VERSION 5.7 ;
  NOWIREEXTENSIONATPIN ON ;
  DIVIDERCHAR "/" ;
  BUSBITCHARS "[]" ;
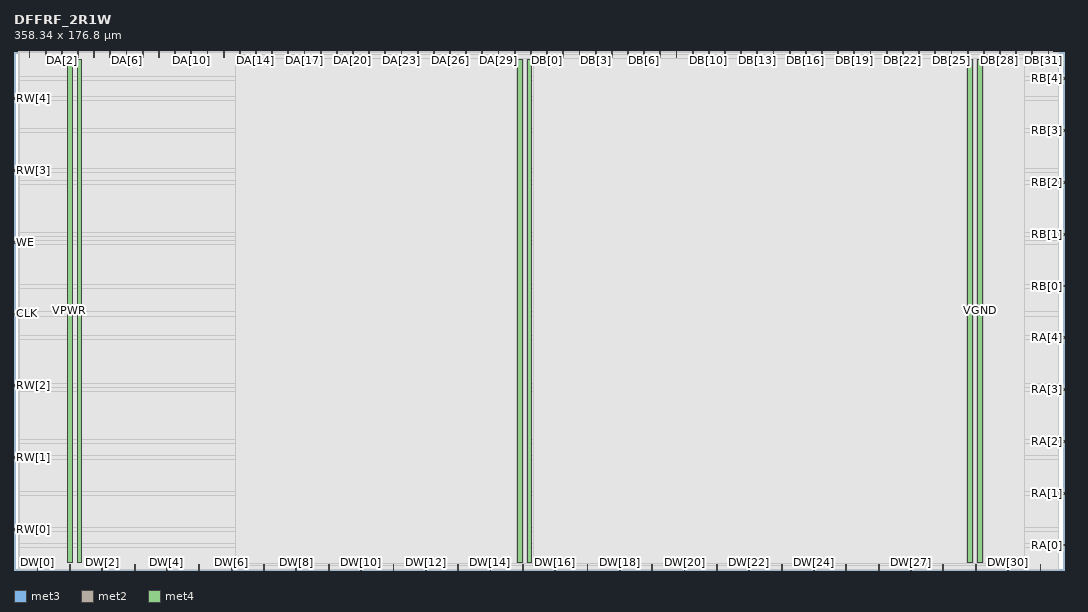
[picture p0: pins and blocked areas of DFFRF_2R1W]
MACRO DFFRF_2R1W
  CLASS BLOCK ;
  FOREIGN DFFRF_2R1W ;
  ORIGIN 0.000 0.000 ;
  SIZE 358.340 BY 176.800 ;
  PIN CLK
    DIRECTION INPUT ;
    USE SIGNAL ;
    ANTENNAGATEAREA 39.431999 ;
    PORT
      LAYER met3 ;
        RECT 0.000 87.080 2.000 87.680 ;
    END
  END CLK
  PIN DA[0]
    DIRECTION OUTPUT ;
    USE SIGNAL ;
    ANTENNADIFFAREA 14.256000 ;
    PORT
      LAYER met2 ;
        RECT 5.150 174.800 5.430 176.800 ;
    END
  END DA[0]
  PIN DA[10]
    DIRECTION OUTPUT ;
    USE SIGNAL ;
    ANTENNADIFFAREA 14.256000 ;
    PORT
      LAYER met2 ;
        RECT 60.350 174.800 60.630 176.800 ;
    END
  END DA[10]
  PIN DA[11]
    DIRECTION OUTPUT ;
    USE SIGNAL ;
    ANTENNADIFFAREA 14.256000 ;
    PORT
      LAYER met2 ;
        RECT 65.870 174.800 66.150 176.800 ;
    END
  END DA[11]
  PIN DA[12]
    DIRECTION OUTPUT ;
    USE SIGNAL ;
    ANTENNADIFFAREA 14.256000 ;
    PORT
      LAYER met2 ;
        RECT 71.390 174.800 71.670 176.800 ;
    END
  END DA[12]
  PIN DA[13]
    DIRECTION OUTPUT ;
    USE SIGNAL ;
    ANTENNADIFFAREA 14.256000 ;
    PORT
      LAYER met2 ;
        RECT 76.910 174.800 77.190 176.800 ;
    END
  END DA[13]
  PIN DA[14]
    DIRECTION OUTPUT ;
    USE SIGNAL ;
    ANTENNADIFFAREA 14.256000 ;
    PORT
      LAYER met2 ;
        RECT 82.430 174.800 82.710 176.800 ;
    END
  END DA[14]
  PIN DA[15]
    DIRECTION OUTPUT ;
    USE SIGNAL ;
    ANTENNADIFFAREA 14.256000 ;
    PORT
      LAYER met2 ;
        RECT 87.950 174.800 88.230 176.800 ;
    END
  END DA[15]
  PIN DA[16]
    DIRECTION OUTPUT ;
    USE SIGNAL ;
    ANTENNADIFFAREA 14.256000 ;
    PORT
      LAYER met2 ;
        RECT 93.470 174.800 93.750 176.800 ;
    END
  END DA[16]
  PIN DA[17]
    DIRECTION OUTPUT ;
    USE SIGNAL ;
    ANTENNADIFFAREA 14.256000 ;
    PORT
      LAYER met2 ;
        RECT 98.990 174.800 99.270 176.800 ;
    END
  END DA[17]
  PIN DA[18]
    DIRECTION OUTPUT ;
    USE SIGNAL ;
    ANTENNADIFFAREA 14.256000 ;
    PORT
      LAYER met2 ;
        RECT 104.510 174.800 104.790 176.800 ;
    END
  END DA[18]
  PIN DA[19]
    DIRECTION OUTPUT ;
    USE SIGNAL ;
    ANTENNADIFFAREA 14.256000 ;
    PORT
      LAYER met2 ;
        RECT 110.030 174.800 110.310 176.800 ;
    END
  END DA[19]
  PIN DA[1]
    DIRECTION OUTPUT ;
    USE SIGNAL ;
    ANTENNADIFFAREA 14.256000 ;
    PORT
      LAYER met2 ;
        RECT 10.670 174.800 10.950 176.800 ;
    END
  END DA[1]
  PIN DA[20]
    DIRECTION OUTPUT ;
    USE SIGNAL ;
    ANTENNADIFFAREA 14.256000 ;
    PORT
      LAYER met2 ;
        RECT 115.550 174.800 115.830 176.800 ;
    END
  END DA[20]
  PIN DA[21]
    DIRECTION OUTPUT ;
    USE SIGNAL ;
    ANTENNADIFFAREA 14.256000 ;
    PORT
      LAYER met2 ;
        RECT 121.070 174.800 121.350 176.800 ;
    END
  END DA[21]
  PIN DA[22]
    DIRECTION OUTPUT ;
    USE SIGNAL ;
    ANTENNADIFFAREA 14.256000 ;
    PORT
      LAYER met2 ;
        RECT 126.590 174.800 126.870 176.800 ;
    END
  END DA[22]
  PIN DA[23]
    DIRECTION OUTPUT ;
    USE SIGNAL ;
    ANTENNADIFFAREA 14.256000 ;
    PORT
      LAYER met2 ;
        RECT 132.110 174.800 132.390 176.800 ;
    END
  END DA[23]
  PIN DA[24]
    DIRECTION OUTPUT ;
    USE SIGNAL ;
    ANTENNADIFFAREA 14.256000 ;
    PORT
      LAYER met2 ;
        RECT 137.630 174.800 137.910 176.800 ;
    END
  END DA[24]
  PIN DA[25]
    DIRECTION OUTPUT ;
    USE SIGNAL ;
    ANTENNADIFFAREA 14.256000 ;
    PORT
      LAYER met2 ;
        RECT 143.150 174.800 143.430 176.800 ;
    END
  END DA[25]
  PIN DA[26]
    DIRECTION OUTPUT ;
    USE SIGNAL ;
    ANTENNADIFFAREA 14.256000 ;
    PORT
      LAYER met2 ;
        RECT 148.670 174.800 148.950 176.800 ;
    END
  END DA[26]
  PIN DA[27]
    DIRECTION OUTPUT ;
    USE SIGNAL ;
    ANTENNADIFFAREA 14.256000 ;
    PORT
      LAYER met2 ;
        RECT 154.190 174.800 154.470 176.800 ;
    END
  END DA[27]
  PIN DA[28]
    DIRECTION OUTPUT ;
    USE SIGNAL ;
    ANTENNADIFFAREA 14.256000 ;
    PORT
      LAYER met2 ;
        RECT 159.710 174.800 159.990 176.800 ;
    END
  END DA[28]
  PIN DA[29]
    DIRECTION OUTPUT ;
    USE SIGNAL ;
    ANTENNADIFFAREA 14.256000 ;
    PORT
      LAYER met2 ;
        RECT 165.230 174.800 165.510 176.800 ;
    END
  END DA[29]
  PIN DA[2]
    DIRECTION OUTPUT ;
    USE SIGNAL ;
    ANTENNADIFFAREA 14.256000 ;
    PORT
      LAYER met2 ;
        RECT 16.190 174.800 16.470 176.800 ;
    END
  END DA[2]
  PIN DA[30]
    DIRECTION OUTPUT ;
    USE SIGNAL ;
    ANTENNADIFFAREA 14.256000 ;
    PORT
      LAYER met2 ;
        RECT 170.750 174.800 171.030 176.800 ;
    END
  END DA[30]
  PIN DA[31]
    DIRECTION OUTPUT ;
    USE SIGNAL ;
    ANTENNADIFFAREA 14.256000 ;
    PORT
      LAYER met2 ;
        RECT 176.270 174.800 176.550 176.800 ;
    END
  END DA[31]
  PIN DA[3]
    DIRECTION OUTPUT ;
    USE SIGNAL ;
    ANTENNADIFFAREA 14.256000 ;
    PORT
      LAYER met2 ;
        RECT 21.710 174.800 21.990 176.800 ;
    END
  END DA[3]
  PIN DA[4]
    DIRECTION OUTPUT ;
    USE SIGNAL ;
    ANTENNADIFFAREA 14.256000 ;
    PORT
      LAYER met2 ;
        RECT 27.230 174.800 27.510 176.800 ;
    END
  END DA[4]
  PIN DA[5]
    DIRECTION OUTPUT ;
    USE SIGNAL ;
    ANTENNADIFFAREA 14.256000 ;
    PORT
      LAYER met2 ;
        RECT 32.750 174.800 33.030 176.800 ;
    END
  END DA[5]
  PIN DA[6]
    DIRECTION OUTPUT ;
    USE SIGNAL ;
    ANTENNADIFFAREA 14.256000 ;
    PORT
      LAYER met2 ;
        RECT 38.270 174.800 38.550 176.800 ;
    END
  END DA[6]
  PIN DA[7]
    DIRECTION OUTPUT ;
    USE SIGNAL ;
    ANTENNADIFFAREA 14.256000 ;
    PORT
      LAYER met2 ;
        RECT 43.790 174.800 44.070 176.800 ;
    END
  END DA[7]
  PIN DA[8]
    DIRECTION OUTPUT ;
    USE SIGNAL ;
    ANTENNADIFFAREA 14.256000 ;
    PORT
      LAYER met2 ;
        RECT 49.310 174.800 49.590 176.800 ;
    END
  END DA[8]
  PIN DA[9]
    DIRECTION OUTPUT ;
    USE SIGNAL ;
    ANTENNADIFFAREA 14.256000 ;
    PORT
      LAYER met2 ;
        RECT 54.830 174.800 55.110 176.800 ;
    END
  END DA[9]
  PIN DB[0]
    DIRECTION OUTPUT ;
    USE SIGNAL ;
    ANTENNADIFFAREA 14.256000 ;
    PORT
      LAYER met2 ;
        RECT 181.790 174.800 182.070 176.800 ;
    END
  END DB[0]
  PIN DB[10]
    DIRECTION OUTPUT ;
    USE SIGNAL ;
    ANTENNADIFFAREA 14.256000 ;
    PORT
      LAYER met2 ;
        RECT 236.990 174.800 237.270 176.800 ;
    END
  END DB[10]
  PIN DB[11]
    DIRECTION OUTPUT ;
    USE SIGNAL ;
    ANTENNADIFFAREA 14.256000 ;
    PORT
      LAYER met2 ;
        RECT 242.510 174.800 242.790 176.800 ;
    END
  END DB[11]
  PIN DB[12]
    DIRECTION OUTPUT ;
    USE SIGNAL ;
    ANTENNADIFFAREA 14.256000 ;
    PORT
      LAYER met2 ;
        RECT 248.030 174.800 248.310 176.800 ;
    END
  END DB[12]
  PIN DB[13]
    DIRECTION OUTPUT ;
    USE SIGNAL ;
    ANTENNADIFFAREA 14.256000 ;
    PORT
      LAYER met2 ;
        RECT 253.550 174.800 253.830 176.800 ;
    END
  END DB[13]
  PIN DB[14]
    DIRECTION OUTPUT ;
    USE SIGNAL ;
    ANTENNADIFFAREA 14.256000 ;
    PORT
      LAYER met2 ;
        RECT 259.070 174.800 259.350 176.800 ;
    END
  END DB[14]
  PIN DB[15]
    DIRECTION OUTPUT ;
    USE SIGNAL ;
    ANTENNADIFFAREA 14.256000 ;
    PORT
      LAYER met2 ;
        RECT 264.590 174.800 264.870 176.800 ;
    END
  END DB[15]
  PIN DB[16]
    DIRECTION OUTPUT ;
    USE SIGNAL ;
    ANTENNADIFFAREA 14.256000 ;
    PORT
      LAYER met2 ;
        RECT 270.110 174.800 270.390 176.800 ;
    END
  END DB[16]
  PIN DB[17]
    DIRECTION OUTPUT ;
    USE SIGNAL ;
    ANTENNADIFFAREA 14.256000 ;
    PORT
      LAYER met2 ;
        RECT 275.630 174.800 275.910 176.800 ;
    END
  END DB[17]
  PIN DB[18]
    DIRECTION OUTPUT ;
    USE SIGNAL ;
    ANTENNADIFFAREA 14.256000 ;
    PORT
      LAYER met2 ;
        RECT 281.150 174.800 281.430 176.800 ;
    END
  END DB[18]
  PIN DB[19]
    DIRECTION OUTPUT ;
    USE SIGNAL ;
    ANTENNADIFFAREA 14.256000 ;
    PORT
      LAYER met2 ;
        RECT 286.670 174.800 286.950 176.800 ;
    END
  END DB[19]
  PIN DB[1]
    DIRECTION OUTPUT ;
    USE SIGNAL ;
    ANTENNADIFFAREA 14.256000 ;
    PORT
      LAYER met2 ;
        RECT 187.310 174.800 187.590 176.800 ;
    END
  END DB[1]
  PIN DB[20]
    DIRECTION OUTPUT ;
    USE SIGNAL ;
    ANTENNADIFFAREA 14.256000 ;
    PORT
      LAYER met2 ;
        RECT 292.190 174.800 292.470 176.800 ;
    END
  END DB[20]
  PIN DB[21]
    DIRECTION OUTPUT ;
    USE SIGNAL ;
    ANTENNADIFFAREA 14.256000 ;
    PORT
      LAYER met2 ;
        RECT 297.710 174.800 297.990 176.800 ;
    END
  END DB[21]
  PIN DB[22]
    DIRECTION OUTPUT ;
    USE SIGNAL ;
    ANTENNADIFFAREA 14.256000 ;
    PORT
      LAYER met2 ;
        RECT 303.230 174.800 303.510 176.800 ;
    END
  END DB[22]
  PIN DB[23]
    DIRECTION OUTPUT ;
    USE SIGNAL ;
    ANTENNADIFFAREA 14.256000 ;
    PORT
      LAYER met2 ;
        RECT 308.750 174.800 309.030 176.800 ;
    END
  END DB[23]
  PIN DB[24]
    DIRECTION OUTPUT ;
    USE SIGNAL ;
    ANTENNADIFFAREA 14.256000 ;
    PORT
      LAYER met2 ;
        RECT 314.270 174.800 314.550 176.800 ;
    END
  END DB[24]
  PIN DB[25]
    DIRECTION OUTPUT ;
    USE SIGNAL ;
    ANTENNADIFFAREA 14.256000 ;
    PORT
      LAYER met2 ;
        RECT 319.790 174.800 320.070 176.800 ;
    END
  END DB[25]
  PIN DB[26]
    DIRECTION OUTPUT ;
    USE SIGNAL ;
    ANTENNADIFFAREA 14.256000 ;
    PORT
      LAYER met2 ;
        RECT 325.310 174.800 325.590 176.800 ;
    END
  END DB[26]
  PIN DB[27]
    DIRECTION OUTPUT ;
    USE SIGNAL ;
    ANTENNADIFFAREA 14.256000 ;
    PORT
      LAYER met2 ;
        RECT 330.830 174.800 331.110 176.800 ;
    END
  END DB[27]
  PIN DB[28]
    DIRECTION OUTPUT ;
    USE SIGNAL ;
    ANTENNADIFFAREA 14.256000 ;
    PORT
      LAYER met2 ;
        RECT 336.350 174.800 336.630 176.800 ;
    END
  END DB[28]
  PIN DB[29]
    DIRECTION OUTPUT ;
    USE SIGNAL ;
    ANTENNADIFFAREA 14.256000 ;
    PORT
      LAYER met2 ;
        RECT 341.870 174.800 342.150 176.800 ;
    END
  END DB[29]
  PIN DB[2]
    DIRECTION OUTPUT ;
    USE SIGNAL ;
    ANTENNADIFFAREA 14.256000 ;
    PORT
      LAYER met2 ;
        RECT 192.830 174.800 193.110 176.800 ;
    END
  END DB[2]
  PIN DB[30]
    DIRECTION OUTPUT ;
    USE SIGNAL ;
    ANTENNADIFFAREA 14.256000 ;
    PORT
      LAYER met2 ;
        RECT 347.390 174.800 347.670 176.800 ;
    END
  END DB[30]
  PIN DB[31]
    DIRECTION OUTPUT ;
    USE SIGNAL ;
    ANTENNADIFFAREA 14.256000 ;
    PORT
      LAYER met2 ;
        RECT 352.910 174.800 353.190 176.800 ;
    END
  END DB[31]
  PIN DB[3]
    DIRECTION OUTPUT ;
    USE SIGNAL ;
    ANTENNADIFFAREA 14.256000 ;
    PORT
      LAYER met2 ;
        RECT 198.350 174.800 198.630 176.800 ;
    END
  END DB[3]
  PIN DB[4]
    DIRECTION OUTPUT ;
    USE SIGNAL ;
    ANTENNADIFFAREA 14.256000 ;
    PORT
      LAYER met2 ;
        RECT 203.870 174.800 204.150 176.800 ;
    END
  END DB[4]
  PIN DB[5]
    DIRECTION OUTPUT ;
    USE SIGNAL ;
    ANTENNADIFFAREA 14.256000 ;
    PORT
      LAYER met2 ;
        RECT 209.390 174.800 209.670 176.800 ;
    END
  END DB[5]
  PIN DB[6]
    DIRECTION OUTPUT ;
    USE SIGNAL ;
    ANTENNADIFFAREA 14.256000 ;
    PORT
      LAYER met2 ;
        RECT 214.910 174.800 215.190 176.800 ;
    END
  END DB[6]
  PIN DB[7]
    DIRECTION OUTPUT ;
    USE SIGNAL ;
    ANTENNADIFFAREA 14.256000 ;
    PORT
      LAYER met2 ;
        RECT 220.430 174.800 220.710 176.800 ;
    END
  END DB[7]
  PIN DB[8]
    DIRECTION OUTPUT ;
    USE SIGNAL ;
    ANTENNADIFFAREA 14.256000 ;
    PORT
      LAYER met2 ;
        RECT 225.950 174.800 226.230 176.800 ;
    END
  END DB[8]
  PIN DB[9]
    DIRECTION OUTPUT ;
    USE SIGNAL ;
    ANTENNADIFFAREA 14.256000 ;
    PORT
      LAYER met2 ;
        RECT 231.470 174.800 231.750 176.800 ;
    END
  END DB[9]
  PIN DW[0]
    DIRECTION INPUT ;
    USE SIGNAL ;
    ANTENNAGATEAREA 3.906000 ;
    PORT
      LAYER met2 ;
        RECT 7.910 0.000 8.190 2.000 ;
    END
  END DW[0]
  PIN DW[10]
    DIRECTION INPUT ;
    USE SIGNAL ;
    ANTENNAGATEAREA 3.906000 ;
    PORT
      LAYER met2 ;
        RECT 118.310 0.000 118.590 2.000 ;
    END
  END DW[10]
  PIN DW[11]
    DIRECTION INPUT ;
    USE SIGNAL ;
    ANTENNAGATEAREA 3.906000 ;
    PORT
      LAYER met2 ;
        RECT 129.350 0.000 129.630 2.000 ;
    END
  END DW[11]
  PIN DW[12]
    DIRECTION INPUT ;
    USE SIGNAL ;
    ANTENNAGATEAREA 3.906000 ;
    PORT
      LAYER met2 ;
        RECT 140.390 0.000 140.670 2.000 ;
    END
  END DW[12]
  PIN DW[13]
    DIRECTION INPUT ;
    USE SIGNAL ;
    ANTENNAGATEAREA 3.906000 ;
    PORT
      LAYER met2 ;
        RECT 151.430 0.000 151.710 2.000 ;
    END
  END DW[13]
  PIN DW[14]
    DIRECTION INPUT ;
    USE SIGNAL ;
    ANTENNAGATEAREA 3.906000 ;
    PORT
      LAYER met2 ;
        RECT 162.470 0.000 162.750 2.000 ;
    END
  END DW[14]
  PIN DW[15]
    DIRECTION INPUT ;
    USE SIGNAL ;
    ANTENNAGATEAREA 3.906000 ;
    PORT
      LAYER met2 ;
        RECT 173.510 0.000 173.790 2.000 ;
    END
  END DW[15]
  PIN DW[16]
    DIRECTION INPUT ;
    USE SIGNAL ;
    ANTENNAGATEAREA 3.906000 ;
    PORT
      LAYER met2 ;
        RECT 184.550 0.000 184.830 2.000 ;
    END
  END DW[16]
  PIN DW[17]
    DIRECTION INPUT ;
    USE SIGNAL ;
    ANTENNAGATEAREA 3.906000 ;
    PORT
      LAYER met2 ;
        RECT 195.590 0.000 195.870 2.000 ;
    END
  END DW[17]
  PIN DW[18]
    DIRECTION INPUT ;
    USE SIGNAL ;
    ANTENNAGATEAREA 3.906000 ;
    PORT
      LAYER met2 ;
        RECT 206.630 0.000 206.910 2.000 ;
    END
  END DW[18]
  PIN DW[19]
    DIRECTION INPUT ;
    USE SIGNAL ;
    ANTENNAGATEAREA 3.906000 ;
    PORT
      LAYER met2 ;
        RECT 217.670 0.000 217.950 2.000 ;
    END
  END DW[19]
  PIN DW[1]
    DIRECTION INPUT ;
    USE SIGNAL ;
    ANTENNAGATEAREA 3.906000 ;
    PORT
      LAYER met2 ;
        RECT 18.950 0.000 19.230 2.000 ;
    END
  END DW[1]
  PIN DW[20]
    DIRECTION INPUT ;
    USE SIGNAL ;
    ANTENNAGATEAREA 3.906000 ;
    PORT
      LAYER met2 ;
        RECT 228.710 0.000 228.990 2.000 ;
    END
  END DW[20]
  PIN DW[21]
    DIRECTION INPUT ;
    USE SIGNAL ;
    ANTENNAGATEAREA 3.906000 ;
    PORT
      LAYER met2 ;
        RECT 239.750 0.000 240.030 2.000 ;
    END
  END DW[21]
  PIN DW[22]
    DIRECTION INPUT ;
    USE SIGNAL ;
    ANTENNAGATEAREA 3.906000 ;
    PORT
      LAYER met2 ;
        RECT 250.790 0.000 251.070 2.000 ;
    END
  END DW[22]
  PIN DW[23]
    DIRECTION INPUT ;
    USE SIGNAL ;
    ANTENNAGATEAREA 3.906000 ;
    PORT
      LAYER met2 ;
        RECT 261.830 0.000 262.110 2.000 ;
    END
  END DW[23]
  PIN DW[24]
    DIRECTION INPUT ;
    USE SIGNAL ;
    ANTENNAGATEAREA 3.906000 ;
    PORT
      LAYER met2 ;
        RECT 272.870 0.000 273.150 2.000 ;
    END
  END DW[24]
  PIN DW[25]
    DIRECTION INPUT ;
    USE SIGNAL ;
    ANTENNAGATEAREA 3.906000 ;
    PORT
      LAYER met2 ;
        RECT 283.910 0.000 284.190 2.000 ;
    END
  END DW[25]
  PIN DW[26]
    DIRECTION INPUT ;
    USE SIGNAL ;
    ANTENNAGATEAREA 3.906000 ;
    PORT
      LAYER met2 ;
        RECT 294.950 0.000 295.230 2.000 ;
    END
  END DW[26]
  PIN DW[27]
    DIRECTION INPUT ;
    USE SIGNAL ;
    ANTENNAGATEAREA 3.906000 ;
    PORT
      LAYER met2 ;
        RECT 305.990 0.000 306.270 2.000 ;
    END
  END DW[27]
  PIN DW[28]
    DIRECTION INPUT ;
    USE SIGNAL ;
    ANTENNAGATEAREA 3.906000 ;
    PORT
      LAYER met2 ;
        RECT 317.030 0.000 317.310 2.000 ;
    END
  END DW[28]
  PIN DW[29]
    DIRECTION INPUT ;
    USE SIGNAL ;
    ANTENNAGATEAREA 3.906000 ;
    PORT
      LAYER met2 ;
        RECT 328.070 0.000 328.350 2.000 ;
    END
  END DW[29]
  PIN DW[2]
    DIRECTION INPUT ;
    USE SIGNAL ;
    ANTENNAGATEAREA 3.906000 ;
    PORT
      LAYER met2 ;
        RECT 29.990 0.000 30.270 2.000 ;
    END
  END DW[2]
  PIN DW[30]
    DIRECTION INPUT ;
    USE SIGNAL ;
    ANTENNAGATEAREA 3.906000 ;
    PORT
      LAYER met2 ;
        RECT 339.110 0.000 339.390 2.000 ;
    END
  END DW[30]
  PIN DW[31]
    DIRECTION INPUT ;
    USE SIGNAL ;
    ANTENNAGATEAREA 3.906000 ;
    PORT
      LAYER met2 ;
        RECT 350.150 0.000 350.430 2.000 ;
    END
  END DW[31]
  PIN DW[3]
    DIRECTION INPUT ;
    USE SIGNAL ;
    ANTENNAGATEAREA 3.906000 ;
    PORT
      LAYER met2 ;
        RECT 41.030 0.000 41.310 2.000 ;
    END
  END DW[3]
  PIN DW[4]
    DIRECTION INPUT ;
    USE SIGNAL ;
    ANTENNAGATEAREA 3.906000 ;
    PORT
      LAYER met2 ;
        RECT 52.070 0.000 52.350 2.000 ;
    END
  END DW[4]
  PIN DW[5]
    DIRECTION INPUT ;
    USE SIGNAL ;
    ANTENNAGATEAREA 3.906000 ;
    PORT
      LAYER met2 ;
        RECT 63.110 0.000 63.390 2.000 ;
    END
  END DW[5]
  PIN DW[6]
    DIRECTION INPUT ;
    USE SIGNAL ;
    ANTENNAGATEAREA 3.906000 ;
    PORT
      LAYER met2 ;
        RECT 74.150 0.000 74.430 2.000 ;
    END
  END DW[6]
  PIN DW[7]
    DIRECTION INPUT ;
    USE SIGNAL ;
    ANTENNAGATEAREA 3.906000 ;
    PORT
      LAYER met2 ;
        RECT 85.190 0.000 85.470 2.000 ;
    END
  END DW[7]
  PIN DW[8]
    DIRECTION INPUT ;
    USE SIGNAL ;
    ANTENNAGATEAREA 3.906000 ;
    PORT
      LAYER met2 ;
        RECT 96.230 0.000 96.510 2.000 ;
    END
  END DW[8]
  PIN DW[9]
    DIRECTION INPUT ;
    USE SIGNAL ;
    ANTENNAGATEAREA 3.906000 ;
    PORT
      LAYER met2 ;
        RECT 107.270 0.000 107.550 2.000 ;
    END
  END DW[9]
  PIN RA[0]
    DIRECTION INPUT ;
    USE SIGNAL ;
    ANTENNAGATEAREA 0.852000 ;
    PORT
      LAYER met3 ;
        RECT 356.340 8.200 358.340 8.800 ;
    END
  END RA[0]
  PIN RA[1]
    DIRECTION INPUT ;
    USE SIGNAL ;
    ANTENNAGATEAREA 0.852000 ;
    PORT
      LAYER met3 ;
        RECT 356.340 25.880 358.340 26.480 ;
    END
  END RA[1]
  PIN RA[2]
    DIRECTION INPUT ;
    USE SIGNAL ;
    ANTENNAGATEAREA 0.852000 ;
    PORT
      LAYER met3 ;
        RECT 356.340 43.560 358.340 44.160 ;
    END
  END RA[2]
  PIN RA[3]
    DIRECTION INPUT ;
    USE SIGNAL ;
    ANTENNAGATEAREA 0.873000 ;
    PORT
      LAYER met3 ;
        RECT 356.340 61.240 358.340 61.840 ;
    END
  END RA[3]
  PIN RA[4]
    DIRECTION INPUT ;
    USE SIGNAL ;
    ANTENNAGATEAREA 0.873000 ;
    PORT
      LAYER met3 ;
        RECT 356.340 78.920 358.340 79.520 ;
    END
  END RA[4]
  PIN RB[0]
    DIRECTION INPUT ;
    USE SIGNAL ;
    ANTENNAGATEAREA 0.852000 ;
    PORT
      LAYER met3 ;
        RECT 356.340 96.600 358.340 97.200 ;
    END
  END RB[0]
  PIN RB[1]
    DIRECTION INPUT ;
    USE SIGNAL ;
    ANTENNAGATEAREA 0.852000 ;
    PORT
      LAYER met3 ;
        RECT 356.340 114.280 358.340 114.880 ;
    END
  END RB[1]
  PIN RB[2]
    DIRECTION INPUT ;
    USE SIGNAL ;
    ANTENNAGATEAREA 0.852000 ;
    PORT
      LAYER met3 ;
        RECT 356.340 131.960 358.340 132.560 ;
    END
  END RB[2]
  PIN RB[3]
    DIRECTION INPUT ;
    USE SIGNAL ;
    ANTENNAGATEAREA 0.873000 ;
    PORT
      LAYER met3 ;
        RECT 356.340 149.640 358.340 150.240 ;
    END
  END RB[3]
  PIN RB[4]
    DIRECTION INPUT ;
    USE SIGNAL ;
    ANTENNAGATEAREA 0.873000 ;
    PORT
      LAYER met3 ;
        RECT 356.340 167.320 358.340 167.920 ;
    END
  END RB[4]
  PIN RW[0]
    DIRECTION INPUT ;
    USE SIGNAL ;
    ANTENNAGATEAREA 0.852000 ;
    PORT
      LAYER met3 ;
        RECT 0.000 13.640 2.000 14.240 ;
    END
  END RW[0]
  PIN RW[1]
    DIRECTION INPUT ;
    USE SIGNAL ;
    ANTENNAGATEAREA 0.852000 ;
    PORT
      LAYER met3 ;
        RECT 0.000 38.120 2.000 38.720 ;
    END
  END RW[1]
  PIN RW[2]
    DIRECTION INPUT ;
    USE SIGNAL ;
    ANTENNAGATEAREA 0.852000 ;
    PORT
      LAYER met3 ;
        RECT 0.000 62.600 2.000 63.200 ;
    END
  END RW[2]
  PIN RW[3]
    DIRECTION INPUT ;
    USE SIGNAL ;
    ANTENNAGATEAREA 0.873000 ;
    PORT
      LAYER met3 ;
        RECT 0.000 136.040 2.000 136.640 ;
    END
  END RW[3]
  PIN RW[4]
    DIRECTION INPUT ;
    USE SIGNAL ;
    ANTENNAGATEAREA 0.873000 ;
    PORT
      LAYER met3 ;
        RECT 0.000 160.520 2.000 161.120 ;
    END
  END RW[4]
  PIN VGND
    DIRECTION INOUT ;
    USE GROUND ;
    PORT
      LAYER met4 ;
        RECT 21.580 2.480 23.180 174.320 ;
    END
    PORT
      LAYER met4 ;
        RECT 175.180 2.480 176.780 174.320 ;
    END
    PORT
      LAYER met4 ;
        RECT 328.780 2.480 330.380 174.320 ;
    END
  END VGND
  PIN VPWR
    DIRECTION INOUT ;
    USE POWER ;
    PORT
      LAYER met4 ;
        RECT 18.280 2.480 19.880 174.320 ;
    END
    PORT
      LAYER met4 ;
        RECT 171.880 2.480 173.480 174.320 ;
    END
    PORT
      LAYER met4 ;
        RECT 325.480 2.480 327.080 174.320 ;
    END
  END VPWR
  PIN WE
    DIRECTION INPUT ;
    USE SIGNAL ;
    ANTENNAGATEAREA 3.906000 ;
    PORT
      LAYER met3 ;
        RECT 0.000 111.560 2.000 112.160 ;
    END
  END WE
  OBS
      LAYER nwell ;
        RECT 2.570 2.635 355.770 174.270 ;
      LAYER li1 ;
        RECT 2.760 2.635 355.580 174.165 ;
      LAYER met1 ;
        RECT 1.450 0.040 355.580 176.760 ;
      LAYER met2 ;
        RECT 1.480 174.520 4.870 176.790 ;
        RECT 5.710 174.520 10.390 176.790 ;
        RECT 11.230 174.520 15.910 176.790 ;
        RECT 16.750 174.520 21.430 176.790 ;
        RECT 22.270 174.520 26.950 176.790 ;
        RECT 27.790 174.520 32.470 176.790 ;
        RECT 33.310 174.520 37.990 176.790 ;
        RECT 38.830 174.520 43.510 176.790 ;
        RECT 44.350 174.520 49.030 176.790 ;
        RECT 49.870 174.520 54.550 176.790 ;
        RECT 55.390 174.520 60.070 176.790 ;
        RECT 60.910 174.520 65.590 176.790 ;
        RECT 66.430 174.520 71.110 176.790 ;
        RECT 71.950 174.520 76.630 176.790 ;
        RECT 77.470 174.520 82.150 176.790 ;
        RECT 82.990 174.520 87.670 176.790 ;
        RECT 88.510 174.520 93.190 176.790 ;
        RECT 94.030 174.520 98.710 176.790 ;
        RECT 99.550 174.520 104.230 176.790 ;
        RECT 105.070 174.520 109.750 176.790 ;
        RECT 110.590 174.520 115.270 176.790 ;
        RECT 116.110 174.520 120.790 176.790 ;
        RECT 121.630 174.520 126.310 176.790 ;
        RECT 127.150 174.520 131.830 176.790 ;
        RECT 132.670 174.520 137.350 176.790 ;
        RECT 138.190 174.520 142.870 176.790 ;
        RECT 143.710 174.520 148.390 176.790 ;
        RECT 149.230 174.520 153.910 176.790 ;
        RECT 154.750 174.520 159.430 176.790 ;
        RECT 160.270 174.520 164.950 176.790 ;
        RECT 165.790 174.520 170.470 176.790 ;
        RECT 171.310 174.520 175.990 176.790 ;
        RECT 176.830 174.520 181.510 176.790 ;
        RECT 182.350 174.520 187.030 176.790 ;
        RECT 187.870 174.520 192.550 176.790 ;
        RECT 193.390 174.520 198.070 176.790 ;
        RECT 198.910 174.520 203.590 176.790 ;
        RECT 204.430 174.520 209.110 176.790 ;
        RECT 209.950 174.520 214.630 176.790 ;
        RECT 215.470 174.520 220.150 176.790 ;
        RECT 220.990 174.520 225.670 176.790 ;
        RECT 226.510 174.520 231.190 176.790 ;
        RECT 232.030 174.520 236.710 176.790 ;
        RECT 237.550 174.520 242.230 176.790 ;
        RECT 243.070 174.520 247.750 176.790 ;
        RECT 248.590 174.520 253.270 176.790 ;
        RECT 254.110 174.520 258.790 176.790 ;
        RECT 259.630 174.520 264.310 176.790 ;
        RECT 265.150 174.520 269.830 176.790 ;
        RECT 270.670 174.520 275.350 176.790 ;
        RECT 276.190 174.520 280.870 176.790 ;
        RECT 281.710 174.520 286.390 176.790 ;
        RECT 287.230 174.520 291.910 176.790 ;
        RECT 292.750 174.520 297.430 176.790 ;
        RECT 298.270 174.520 302.950 176.790 ;
        RECT 303.790 174.520 308.470 176.790 ;
        RECT 309.310 174.520 313.990 176.790 ;
        RECT 314.830 174.520 319.510 176.790 ;
        RECT 320.350 174.520 325.030 176.790 ;
        RECT 325.870 174.520 330.550 176.790 ;
        RECT 331.390 174.520 336.070 176.790 ;
        RECT 336.910 174.520 341.590 176.790 ;
        RECT 342.430 174.520 347.110 176.790 ;
        RECT 347.950 174.520 352.630 176.790 ;
        RECT 353.470 174.520 354.560 176.790 ;
        RECT 1.480 2.280 354.560 174.520 ;
        RECT 1.480 0.010 7.630 2.280 ;
        RECT 8.470 0.010 18.670 2.280 ;
        RECT 19.510 0.010 29.710 2.280 ;
        RECT 30.550 0.010 40.750 2.280 ;
        RECT 41.590 0.010 51.790 2.280 ;
        RECT 52.630 0.010 62.830 2.280 ;
        RECT 63.670 0.010 73.870 2.280 ;
        RECT 74.710 0.010 84.910 2.280 ;
        RECT 85.750 0.010 95.950 2.280 ;
        RECT 96.790 0.010 106.990 2.280 ;
        RECT 107.830 0.010 118.030 2.280 ;
        RECT 118.870 0.010 129.070 2.280 ;
        RECT 129.910 0.010 140.110 2.280 ;
        RECT 140.950 0.010 151.150 2.280 ;
        RECT 151.990 0.010 162.190 2.280 ;
        RECT 163.030 0.010 173.230 2.280 ;
        RECT 174.070 0.010 184.270 2.280 ;
        RECT 185.110 0.010 195.310 2.280 ;
        RECT 196.150 0.010 206.350 2.280 ;
        RECT 207.190 0.010 217.390 2.280 ;
        RECT 218.230 0.010 228.430 2.280 ;
        RECT 229.270 0.010 239.470 2.280 ;
        RECT 240.310 0.010 250.510 2.280 ;
        RECT 251.350 0.010 261.550 2.280 ;
        RECT 262.390 0.010 272.590 2.280 ;
        RECT 273.430 0.010 283.630 2.280 ;
        RECT 284.470 0.010 294.670 2.280 ;
        RECT 295.510 0.010 305.710 2.280 ;
        RECT 306.550 0.010 316.750 2.280 ;
        RECT 317.590 0.010 327.790 2.280 ;
        RECT 328.630 0.010 338.830 2.280 ;
        RECT 339.670 0.010 349.870 2.280 ;
        RECT 350.710 0.010 354.560 2.280 ;
      LAYER met3 ;
        RECT 2.000 168.320 356.340 176.625 ;
        RECT 2.000 166.920 355.940 168.320 ;
        RECT 2.000 161.520 356.340 166.920 ;
        RECT 2.400 160.120 356.340 161.520 ;
        RECT 2.000 150.640 356.340 160.120 ;
        RECT 2.000 149.240 355.940 150.640 ;
        RECT 2.000 137.040 356.340 149.240 ;
        RECT 2.400 135.640 356.340 137.040 ;
        RECT 2.000 132.960 356.340 135.640 ;
        RECT 2.000 131.560 355.940 132.960 ;
        RECT 2.000 115.280 356.340 131.560 ;
        RECT 2.000 113.880 355.940 115.280 ;
        RECT 2.000 112.560 356.340 113.880 ;
        RECT 2.400 111.160 356.340 112.560 ;
        RECT 2.000 97.600 356.340 111.160 ;
        RECT 2.000 96.200 355.940 97.600 ;
        RECT 2.000 88.080 356.340 96.200 ;
        RECT 2.400 86.680 356.340 88.080 ;
        RECT 2.000 79.920 356.340 86.680 ;
        RECT 2.000 78.520 355.940 79.920 ;
        RECT 2.000 63.600 356.340 78.520 ;
        RECT 2.400 62.240 356.340 63.600 ;
        RECT 2.400 62.200 355.940 62.240 ;
        RECT 2.000 60.840 355.940 62.200 ;
        RECT 2.000 44.560 356.340 60.840 ;
        RECT 2.000 43.160 355.940 44.560 ;
        RECT 2.000 39.120 356.340 43.160 ;
        RECT 2.400 37.720 356.340 39.120 ;
        RECT 2.000 26.880 356.340 37.720 ;
        RECT 2.000 25.480 355.940 26.880 ;
        RECT 2.000 14.640 356.340 25.480 ;
        RECT 2.400 13.240 356.340 14.640 ;
        RECT 2.000 9.200 356.340 13.240 ;
        RECT 2.000 7.800 355.940 9.200 ;
        RECT 2.000 0.175 356.340 7.800 ;
      LAYER met4 ;
        RECT 75.735 174.720 344.705 175.945 ;
        RECT 75.735 2.080 171.480 174.720 ;
        RECT 173.880 2.080 174.780 174.720 ;
        RECT 177.180 2.080 325.080 174.720 ;
        RECT 327.480 2.080 328.380 174.720 ;
        RECT 330.780 2.080 344.705 174.720 ;
        RECT 75.735 1.535 344.705 2.080 ;
  END
END DFFRF_2R1W
END LIBRARY

